VERSION 5.4 ;
NAMESCASESENSITIVE ON ;
BUSBITCHARS "[]" ;
DIVIDERCHAR "/" ;
UNITS
  DATABASE MICRONS 1000 ;
END UNITS
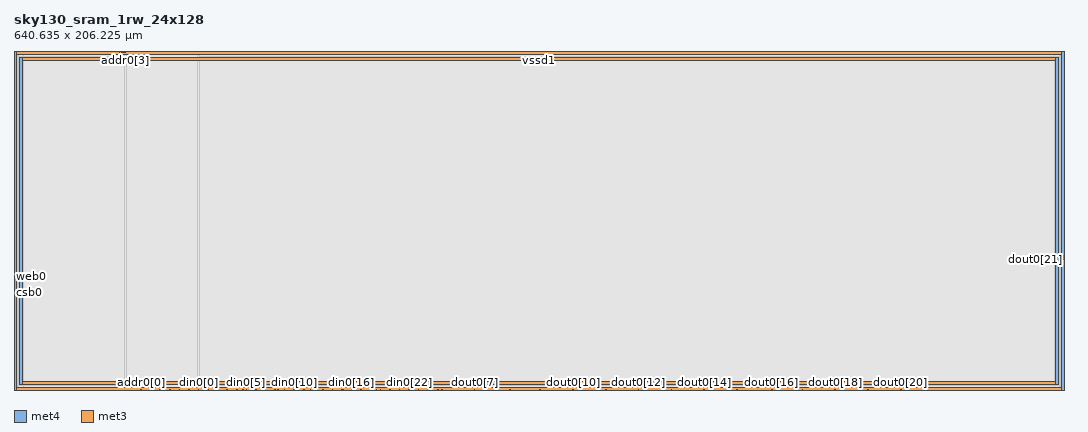
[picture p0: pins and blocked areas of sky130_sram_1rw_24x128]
MACRO sky130_sram_1rw_24x128
   CLASS BLOCK ;
   SIZE 640.635 BY 206.225 ;
   SYMMETRY X Y R90 ;
   PIN din0[0]
      DIRECTION INPUT ;
      PORT
         LAYER met4 ;
         RECT  112.4 0.0 112.78 0.38 ;
      END
   END din0[0]
   PIN din0[1]
      DIRECTION INPUT ;
      PORT
         LAYER met4 ;
         RECT  118.24 0.0 118.62 0.38 ;
      END
   END din0[1]
   PIN din0[2]
      DIRECTION INPUT ;
      PORT
         LAYER met4 ;
         RECT  124.08 0.0 124.46 0.38 ;
      END
   END din0[2]
   PIN din0[3]
      DIRECTION INPUT ;
      PORT
         LAYER met4 ;
         RECT  129.92 0.0 130.3 0.38 ;
      END
   END din0[3]
   PIN din0[4]
      DIRECTION INPUT ;
      PORT
         LAYER met4 ;
         RECT  135.76 0.0 136.14 0.38 ;
      END
   END din0[4]
   PIN din0[5]
      DIRECTION INPUT ;
      PORT
         LAYER met4 ;
         RECT  141.6 0.0 141.98 0.38 ;
      END
   END din0[5]
   PIN din0[6]
      DIRECTION INPUT ;
      PORT
         LAYER met4 ;
         RECT  147.44 0.0 147.82 0.38 ;
      END
   END din0[6]
   PIN din0[7]
      DIRECTION INPUT ;
      PORT
         LAYER met4 ;
         RECT  153.28 0.0 153.66 0.38 ;
      END
   END din0[7]
   PIN din0[8]
      DIRECTION INPUT ;
      PORT
         LAYER met4 ;
         RECT  159.12 0.0 159.5 0.38 ;
      END
   END din0[8]
   PIN din0[9]
      DIRECTION INPUT ;
      PORT
         LAYER met4 ;
         RECT  164.96 0.0 165.34 0.38 ;
      END
   END din0[9]
   PIN din0[10]
      DIRECTION INPUT ;
      PORT
         LAYER met4 ;
         RECT  170.8 0.0 171.18 0.38 ;
      END
   END din0[10]
   PIN din0[11]
      DIRECTION INPUT ;
      PORT
         LAYER met4 ;
         RECT  176.64 0.0 177.02 0.38 ;
      END
   END din0[11]
   PIN din0[12]
      DIRECTION INPUT ;
      PORT
         LAYER met4 ;
         RECT  182.48 0.0 182.86 0.38 ;
      END
   END din0[12]
   PIN din0[13]
      DIRECTION INPUT ;
      PORT
         LAYER met4 ;
         RECT  188.32 0.0 188.7 0.38 ;
      END
   END din0[13]
   PIN din0[14]
      DIRECTION INPUT ;
      PORT
         LAYER met4 ;
         RECT  194.16 0.0 194.54 0.38 ;
      END
   END din0[14]
   PIN din0[15]
      DIRECTION INPUT ;
      PORT
         LAYER met4 ;
         RECT  200.0 0.0 200.38 0.38 ;
      END
   END din0[15]
   PIN din0[16]
      DIRECTION INPUT ;
      PORT
         LAYER met4 ;
         RECT  205.84 0.0 206.22 0.38 ;
      END
   END din0[16]
   PIN din0[17]
      DIRECTION INPUT ;
      PORT
         LAYER met4 ;
         RECT  211.68 0.0 212.06 0.38 ;
      END
   END din0[17]
   PIN din0[18]
      DIRECTION INPUT ;
      PORT
         LAYER met4 ;
         RECT  217.52 0.0 217.9 0.38 ;
      END
   END din0[18]
   PIN din0[19]
      DIRECTION INPUT ;
      PORT
         LAYER met4 ;
         RECT  223.36 0.0 223.74 0.38 ;
      END
   END din0[19]
   PIN din0[20]
      DIRECTION INPUT ;
      PORT
         LAYER met4 ;
         RECT  229.2 0.0 229.58 0.38 ;
      END
   END din0[20]
   PIN din0[21]
      DIRECTION INPUT ;
      PORT
         LAYER met4 ;
         RECT  235.04 0.0 235.42 0.38 ;
      END
   END din0[21]
   PIN din0[22]
      DIRECTION INPUT ;
      PORT
         LAYER met4 ;
         RECT  240.88 0.0 241.26 0.38 ;
      END
   END din0[22]
   PIN din0[23]
      DIRECTION INPUT ;
      PORT
         LAYER met4 ;
         RECT  246.72 0.0 247.1 0.38 ;
      END
   END din0[23]
   PIN din0[24]
      DIRECTION INPUT ;
      PORT
         LAYER met4 ;
         RECT  252.56 0.0 252.94 0.38 ;
      END
   END din0[24]
   PIN addr0[0]
      DIRECTION INPUT ;
      PORT
         LAYER met4 ;
         RECT  77.36 0.0 77.74 0.38 ;
      END
   END addr0[0]
   PIN addr0[1]
      DIRECTION INPUT ;
      PORT
         LAYER met4 ;
         RECT  83.2 0.0 83.58 0.38 ;
      END
   END addr0[1]
   PIN addr0[2]
      DIRECTION INPUT ;
      PORT
         LAYER met4 ;
         RECT  89.04 0.0 89.42 0.38 ;
      END
   END addr0[2]
   PIN addr0[3]
      DIRECTION INPUT ;
      PORT
         LAYER met4 ;
         RECT  67.805 205.845 68.185 206.225 ;
      END
   END addr0[3]
   PIN addr0[4]
      DIRECTION INPUT ;
      PORT
         LAYER met4 ;
         RECT  64.14 205.845 64.52 206.225 ;
      END
   END addr0[4]
   PIN addr0[5]
      DIRECTION INPUT ;
      PORT
         LAYER met4 ;
         RECT  67.115 205.845 67.495 206.225 ;
      END
   END addr0[5]
   PIN addr0[6]
      DIRECTION INPUT ;
      PORT
         LAYER met4 ;
         RECT  66.425 205.845 66.805 206.225 ;
      END
   END addr0[6]
   PIN addr0[7]
      DIRECTION INPUT ;
      PORT
         LAYER met4 ;
         RECT  65.68 205.845 66.06 206.225 ;
      END
   END addr0[7]
   PIN csb0
      DIRECTION INPUT ;
      PORT
         LAYER met3 ;
         RECT  0.0 59.185 0.38 59.565 ;
      END
   END csb0
   PIN web0
      DIRECTION INPUT ;
      PORT
         LAYER met3 ;
         RECT  0.0 69.075 0.38 69.455 ;
      END
   END web0
   PIN clk0
      DIRECTION INPUT ;
      PORT
         LAYER met3 ;
         RECT  0.0 60.675 0.38 61.055 ;
      END
   END clk0
   PIN wmask0[0]
      DIRECTION INPUT ;
      PORT
         LAYER met4 ;
         RECT  94.88 0.0 95.26 0.38 ;
      END
   END wmask0[0]
   PIN wmask0[1]
      DIRECTION INPUT ;
      PORT
         LAYER met4 ;
         RECT  100.72 0.0 101.1 0.38 ;
      END
   END wmask0[1]
   PIN wmask0[2]
      DIRECTION INPUT ;
      PORT
         LAYER met4 ;
         RECT  106.56 0.0 106.94 0.38 ;
      END
   END wmask0[2]
   PIN spare_wen0
      DIRECTION INPUT ;
      PORT
         LAYER met4 ;
         RECT  258.4 0.0 258.78 0.38 ;
      END
   END spare_wen0
   PIN dout0[0]
      DIRECTION OUTPUT ;
      PORT
         LAYER met4 ;
         RECT  139.615 0.0 139.995 0.38 ;
      END
   END dout0[0]
   PIN dout0[1]
      DIRECTION OUTPUT ;
      PORT
         LAYER met4 ;
         RECT  160.88 0.0 161.26 0.38 ;
      END
   END dout0[1]
   PIN dout0[2]
      DIRECTION OUTPUT ;
      PORT
         LAYER met4 ;
         RECT  180.675 0.0 181.055 0.38 ;
      END
   END dout0[2]
   PIN dout0[3]
      DIRECTION OUTPUT ;
      PORT
         LAYER met4 ;
         RECT  200.88 0.0 201.26 0.38 ;
      END
   END dout0[3]
   PIN dout0[4]
      DIRECTION OUTPUT ;
      PORT
         LAYER met4 ;
         RECT  220.88 0.0 221.26 0.38 ;
      END
   END dout0[4]
   PIN dout0[5]
      DIRECTION OUTPUT ;
      PORT
         LAYER met4 ;
         RECT  241.57 0.0 241.95 0.38 ;
      END
   END dout0[5]
   PIN dout0[6]
      DIRECTION OUTPUT ;
      PORT
         LAYER met4 ;
         RECT  260.88 0.0 261.26 0.38 ;
      END
   END dout0[6]
   PIN dout0[7]
      DIRECTION OUTPUT ;
      PORT
         LAYER met4 ;
         RECT  280.88 0.0 281.26 0.38 ;
      END
   END dout0[7]
   PIN dout0[8]
      DIRECTION OUTPUT ;
      PORT
         LAYER met4 ;
         RECT  302.26 0.0 302.64 0.38 ;
      END
   END dout0[8]
   PIN dout0[9]
      DIRECTION OUTPUT ;
      PORT
         LAYER met4 ;
         RECT  320.88 0.0 321.26 0.38 ;
      END
   END dout0[9]
   PIN dout0[10]
      DIRECTION OUTPUT ;
      PORT
         LAYER met4 ;
         RECT  340.88 0.0 341.26 0.38 ;
      END
   END dout0[10]
   PIN dout0[11]
      DIRECTION OUTPUT ;
      PORT
         LAYER met4 ;
         RECT  360.88 0.0 361.26 0.38 ;
      END
   END dout0[11]
   PIN dout0[12]
      DIRECTION OUTPUT ;
      PORT
         LAYER met4 ;
         RECT  380.88 0.0 381.26 0.38 ;
      END
   END dout0[12]
   PIN dout0[13]
      DIRECTION OUTPUT ;
      PORT
         LAYER met4 ;
         RECT  400.88 0.0 401.26 0.38 ;
      END
   END dout0[13]
   PIN dout0[14]
      DIRECTION OUTPUT ;
      PORT
         LAYER met4 ;
         RECT  420.88 0.0 421.26 0.38 ;
      END
   END dout0[14]
   PIN dout0[15]
      DIRECTION OUTPUT ;
      PORT
         LAYER met4 ;
         RECT  440.88 0.0 441.26 0.38 ;
      END
   END dout0[15]
   PIN dout0[16]
      DIRECTION OUTPUT ;
      PORT
         LAYER met4 ;
         RECT  462.26 0.0 462.64 0.38 ;
      END
   END dout0[16]
   PIN dout0[17]
      DIRECTION OUTPUT ;
      PORT
         LAYER met4 ;
         RECT  480.88 0.0 481.26 0.38 ;
      END
   END dout0[17]
   PIN dout0[18]
      DIRECTION OUTPUT ;
      PORT
         LAYER met4 ;
         RECT  500.88 0.0 501.26 0.38 ;
      END
   END dout0[18]
   PIN dout0[19]
      DIRECTION OUTPUT ;
      PORT
         LAYER met4 ;
         RECT  520.88 0.0 521.26 0.38 ;
      END
   END dout0[19]
   PIN dout0[20]
      DIRECTION OUTPUT ;
      PORT
         LAYER met4 ;
         RECT  540.88 0.0 541.26 0.38 ;
      END
   END dout0[20]
   PIN dout0[21]
      DIRECTION OUTPUT ;
      PORT
         LAYER met3 ;
         RECT  640.255 79.58 640.635 79.96 ;
      END
   END dout0[21]
   PIN dout0[22]
      DIRECTION OUTPUT ;
      PORT
         LAYER met3 ;
         RECT  640.255 80.27 640.635 80.65 ;
      END
   END dout0[22]
   PIN dout0[23]
      DIRECTION OUTPUT ;
      PORT
         LAYER met3 ;
         RECT  640.255 81.76 640.635 82.14 ;
      END
   END dout0[23]
   PIN dout0[24]
      DIRECTION OUTPUT ;
      PORT
         LAYER met3 ;
         RECT  640.255 81.015 640.635 81.395 ;
      END
   END dout0[24]
   PIN vccd1
      DIRECTION INOUT ;
      USE POWER ; 
      SHAPE ABUTMENT ; 
      PORT
         LAYER met4 ;
         RECT  0.0 0.0 1.74 206.225 ;
         LAYER met4 ;
         RECT  638.895 0.0 640.635 206.225 ;
         LAYER met3 ;
         RECT  0.0 204.485 640.635 206.225 ;
         LAYER met3 ;
         RECT  0.0 0.0 640.635 1.74 ;
      END
   END vccd1
   PIN vssd1
      DIRECTION INOUT ;
      USE GROUND ; 
      SHAPE ABUTMENT ; 
      PORT
         LAYER met4 ;
         RECT  3.48 3.48 5.22 202.745 ;
         LAYER met4 ;
         RECT  635.415 3.48 637.155 202.745 ;
         LAYER met3 ;
         RECT  3.48 201.005 637.155 202.745 ;
         LAYER met3 ;
         RECT  3.48 3.48 637.155 5.22 ;
      END
   END vssd1
   OBS
   LAYER  met1 ;
      RECT  0.62 0.62 640.015 205.605 ;
   LAYER  met2 ;
      RECT  0.62 0.62 640.015 205.605 ;
   LAYER  met3 ;
      RECT  0.98 58.585 640.015 60.165 ;
      RECT  0.62 61.655 0.98 68.475 ;
      RECT  0.98 60.165 639.655 78.98 ;
      RECT  0.98 78.98 639.655 80.56 ;
      RECT  639.655 60.165 640.015 78.98 ;
      RECT  0.62 70.055 0.98 203.885 ;
      RECT  639.655 82.74 640.015 203.885 ;
      RECT  0.62 2.34 0.98 58.585 ;
      RECT  0.98 80.56 2.88 200.405 ;
      RECT  0.98 200.405 2.88 203.345 ;
      RECT  0.98 203.345 2.88 203.885 ;
      RECT  2.88 80.56 637.755 200.405 ;
      RECT  2.88 203.345 637.755 203.885 ;
      RECT  637.755 80.56 639.655 200.405 ;
      RECT  637.755 200.405 639.655 203.345 ;
      RECT  637.755 203.345 639.655 203.885 ;
      RECT  0.98 2.34 2.88 2.88 ;
      RECT  0.98 2.88 2.88 5.82 ;
      RECT  0.98 5.82 2.88 58.585 ;
      RECT  2.88 2.34 637.755 2.88 ;
      RECT  2.88 5.82 637.755 58.585 ;
      RECT  637.755 2.34 640.015 2.88 ;
      RECT  637.755 2.88 640.015 5.82 ;
      RECT  637.755 5.82 640.015 58.585 ;
   LAYER  met4 ;
      RECT  111.8 0.98 113.38 205.605 ;
      RECT  113.38 0.62 117.64 0.98 ;
      RECT  119.22 0.62 123.48 0.98 ;
      RECT  125.06 0.62 129.32 0.98 ;
      RECT  130.9 0.62 135.16 0.98 ;
      RECT  142.58 0.62 146.84 0.98 ;
      RECT  148.42 0.62 152.68 0.98 ;
      RECT  154.26 0.62 158.52 0.98 ;
      RECT  165.94 0.62 170.2 0.98 ;
      RECT  171.78 0.62 176.04 0.98 ;
      RECT  183.46 0.62 187.72 0.98 ;
      RECT  189.3 0.62 193.56 0.98 ;
      RECT  195.14 0.62 199.4 0.98 ;
      RECT  206.82 0.62 211.08 0.98 ;
      RECT  212.66 0.62 216.92 0.98 ;
      RECT  224.34 0.62 228.6 0.98 ;
      RECT  230.18 0.62 234.44 0.98 ;
      RECT  236.02 0.62 240.28 0.98 ;
      RECT  247.7 0.62 251.96 0.98 ;
      RECT  78.34 0.62 82.6 0.98 ;
      RECT  84.18 0.62 88.44 0.98 ;
      RECT  67.205 0.98 68.785 205.245 ;
      RECT  68.785 0.98 111.8 205.245 ;
      RECT  68.785 205.245 111.8 205.605 ;
      RECT  90.02 0.62 94.28 0.98 ;
      RECT  95.86 0.62 100.12 0.98 ;
      RECT  101.7 0.62 105.96 0.98 ;
      RECT  107.54 0.62 111.8 0.98 ;
      RECT  253.54 0.62 257.8 0.98 ;
      RECT  136.74 0.62 139.015 0.98 ;
      RECT  140.595 0.62 141.0 0.98 ;
      RECT  160.1 0.62 160.28 0.98 ;
      RECT  161.86 0.62 164.36 0.98 ;
      RECT  177.62 0.62 180.075 0.98 ;
      RECT  181.655 0.62 181.88 0.98 ;
      RECT  201.86 0.62 205.24 0.98 ;
      RECT  218.5 0.62 220.28 0.98 ;
      RECT  221.86 0.62 222.76 0.98 ;
      RECT  242.55 0.62 246.12 0.98 ;
      RECT  259.38 0.62 260.28 0.98 ;
      RECT  261.86 0.62 280.28 0.98 ;
      RECT  281.86 0.62 301.66 0.98 ;
      RECT  303.24 0.62 320.28 0.98 ;
      RECT  321.86 0.62 340.28 0.98 ;
      RECT  341.86 0.62 360.28 0.98 ;
      RECT  361.86 0.62 380.28 0.98 ;
      RECT  381.86 0.62 400.28 0.98 ;
      RECT  401.86 0.62 420.28 0.98 ;
      RECT  421.86 0.62 440.28 0.98 ;
      RECT  441.86 0.62 461.66 0.98 ;
      RECT  463.24 0.62 480.28 0.98 ;
      RECT  481.86 0.62 500.28 0.98 ;
      RECT  501.86 0.62 520.28 0.98 ;
      RECT  521.86 0.62 540.28 0.98 ;
      RECT  2.34 0.62 76.76 0.98 ;
      RECT  2.34 205.245 63.54 205.605 ;
      RECT  541.86 0.62 638.295 0.98 ;
      RECT  2.34 0.98 2.88 2.88 ;
      RECT  2.34 2.88 2.88 203.345 ;
      RECT  2.34 203.345 2.88 205.245 ;
      RECT  2.88 0.98 5.82 2.88 ;
      RECT  2.88 203.345 5.82 205.245 ;
      RECT  5.82 0.98 67.205 2.88 ;
      RECT  5.82 2.88 67.205 203.345 ;
      RECT  5.82 203.345 67.205 205.245 ;
      RECT  113.38 0.98 634.815 2.88 ;
      RECT  113.38 2.88 634.815 203.345 ;
      RECT  113.38 203.345 634.815 205.605 ;
      RECT  634.815 0.98 637.755 2.88 ;
      RECT  634.815 203.345 637.755 205.605 ;
      RECT  637.755 0.98 638.295 2.88 ;
      RECT  637.755 2.88 638.295 203.345 ;
      RECT  637.755 203.345 638.295 205.605 ;
   END
END    sky130_sram_1rw_24x128
END    LIBRARY
